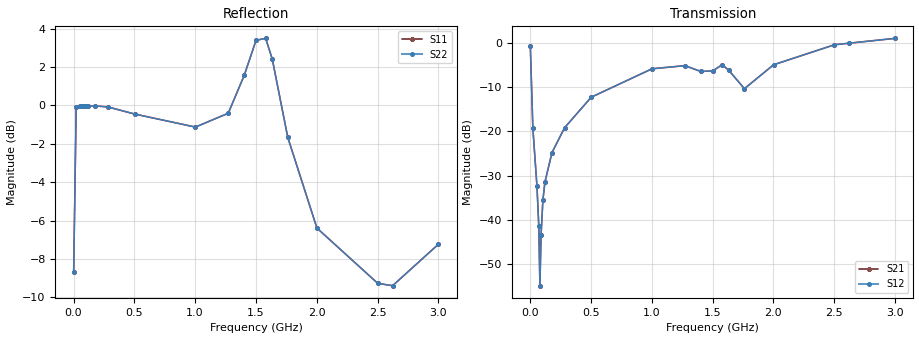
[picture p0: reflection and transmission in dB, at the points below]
!s-Parameter Generated by FASTRON Sdn. Bhd.
!FASTRON P/N : MICC-6R2X
!Keysight Technologies,E4991B,MY54100416,A.01.15
!Date: Fri Aug 28 10:49:29 2026
!Version  : Rev00 Fri Aug 28 10:49:29 2026
!Data & Calibration Information:
!PortZ  Port1:50+j0  Port2:50+j0
!When reading, reference impedance value at option line is always used.
!Remarks : This data is being provided solely for informational purposes.
!Freq	S11	S21	S12	S22
# Hz S dB R 50
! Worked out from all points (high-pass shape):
!   1601 points, 1 MHz to 3 GHz, reference 50 ohm
!   highest |S21| = 1.08 dB at 3 GHz (marker M1); lowest = -54.9 dB at 79.72 MHz (marker M2)
!   |S21| within 3 dB of the highest: start of sweep to 1.745 MHz; 2.244 GHz to end of sweep
!   lowest |S11| = -9.4 dB at 2.623 GHz (marker M3), VSWR 2.03, Z = 44.4 - j33.5 ohm
!   |S11| at or under -10 dB: nowhere
!   |S22| runs from -9.4 to 3.7 dB; largest |S21 - S12| = 0
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1000000  -8.66 67.0  -0.72 -21.6  -0.72 -21.6  -8.66 67.0
2.161812e7  -0.07 6.2  -19.28 -82.7  -19.28 -82.7  -0.07 6.2
5.535688e7  -0.02 1.4  -32.42 -85.1  -32.42 -85.1  -0.02 1.4
7.035188e7  -0.02 0.5  -41.38 -78.0  -41.38 -78.0  -0.02 0.5
7.972375e7  -0.01 0.0  -54.95 -17.2  -54.95 -17.2  -0.01 0.0
8.909562e7  -0.01 -0.4  -43.48 74.9  -43.48 74.9  -0.01 -0.4
1.040906e8  -0.02 -0.9  -35.57 83.3  -35.57 83.3  -0.02 -0.9
1.2096e8  -0.02 -1.5  -31.46 84.8  -31.46 84.8  -0.02 -1.5
1.790656e8  -0.03 -3.3  -24.79 84.8  -24.79 84.8  -0.03 -3.3
2.821562e8  -0.08 -6.3  -19.18 82.1  -19.18 82.1  -0.08 -6.3
5.014581e8  -0.45 -14.1  -12.25 71.0  -12.25 71.0  -0.45 -14.1
1.001916e9  -1.13 -30.8  -5.81 61.4  -5.81 61.4  -1.13 -30.8
1.271826e9  -0.41 -33.0  -5.10 69.0  -5.10 69.0  -0.41 -33.0
1.403032e9  1.56 -22.9  -6.42 102.4  -6.42 102.4  1.56 -22.9
1.5005e9  3.39 -3.8  -6.29 168.3  -6.29 168.3  3.39 -3.8
1.579224e9  3.49 13.3  -4.88 -142.9  -4.88 -142.9  3.49 13.3
1.633581e9  2.42 18.5  -6.19 -121.0  -6.19 -121.0  2.42 18.5
1.761038e9  -1.66 15.8  -10.32 -47.6  -10.32 -47.6  -1.66 15.8
2.000958e9  -6.39 -19.0  -4.90 15.9  -4.90 15.9  -6.39 -19.0
2.501416e9  -9.27 -73.1  -0.37 20.1  -0.37 20.1  -9.27 -73.1
2.623251e9  -9.39 -80.0  -0.01 19.5  -0.01 19.5  -9.39 -80.0
3e9  -7.23 -96.2  1.08 22.4  1.08 22.4  -7.23 -96.2
